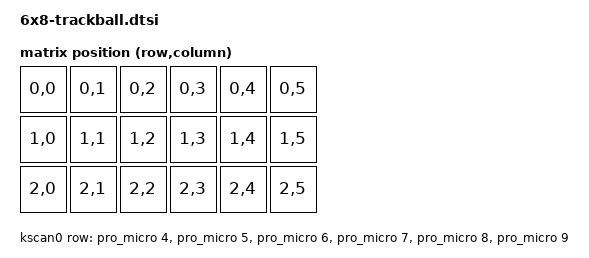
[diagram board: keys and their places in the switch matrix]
#include <dt-bindings/zmk/matrix_transform.h> // Put this with the other includes at the top of your dtsi

/ {
    chosen {
        zephyr,display = &oled;
        zmk,kscan = &kscan0;
        zmk,physical-layout = &kata0510_lily58_layout;
    };

    default_transform: keymap_transform_0 {
        compatible = "zmk,matrix-transform";
        columns = <16>;
        rows = <5>;
//| SW7  | SW6  | SW5  | SW4  | SW3   | SW2  | SW1  |           | SW1  | SW2  | SW3  | SW4  | SW5   | SW6  | SW7  | SW8  |         
//| SW14 | SW13 | SW12 | SW11 | SW10  | SW9  | SW8  |           | SW9  | SW10 | SW11 | SW12 | SW13  | SW14 | SW15 | SW16 | 
//| SW22 | SW21 | SW20 | SW19 | SW18  | SW17 | SW16  | SW15 |   | SW17 | SW18 | SW19 | SW20 | SW21  | SW22 | SW23 | SW24 |         
//| SW30 | SW29 | SW28 | SW27 | SW26  | SW25 | SW24  | SW23 |   | SW25 | SW26 | SW27 | SW28 | SW29  | SW30 | SW31 | SW32 |         
//| SW37 | SW36 | SW35 | SW34 | SW33  | SW32 | SW31  |                 | SW33 | SW34 | SW35 | SW36  | SW37 | SW38 | SW39 |         
//                     | SW39  | SW38 |                                              | SW40 | SW41  |        
//                                    | SW42 | SW41 | SW40 |           | SW42 |      | SW43 |
//                                           | SW44 | SW43 |              | SW44 | SW45 |

/ {
    default_transform: keymap_transform0 {
        compatible = "zmk,matrix-transform";
        columns = <6>;
        rows = <3>;
        map = <
        //  LKey 1 |LKey 2 |LKey 3      RKey 1 |RKey 2 |RKey 3
            RC(0,0) RC(0,1) RC(0,2)     RC(0,3) RC(0,4) RC(0,5)
        //  LKey 4 |LKey 5 |LKey 6      RKey 4 |RKey 5 |RKey 6
            RC(1,0) RC(1,1) RC(1,2)     RC(1,3) RC(1,4) RC(1,5)
        //  LKey 7 |LKey 8 |LKey 9      RKey 7 |RKey 8 |RKey 9
            RC(2,0) RC(2,1) RC(2,2)     RC(2,3) RC(2,4) RC(2,5)
        >;
    };
};

/ {
    kscan0: kscan0 {
        compatible = "zmk,kscan-gpio-matrix";
        diode-direction = "col2row";
        wakeup-source;

        row-gpios
            = <&pro_micro 4 (GPIO_ACTIVE_HIGH | GPIO_PULL_DOWN)>
            , <&pro_micro 5 (GPIO_ACTIVE_HIGH | GPIO_PULL_DOWN)>
            , <&pro_micro 6 (GPIO_ACTIVE_HIGH | GPIO_PULL_DOWN)>
            , <&pro_micro 7 (GPIO_ACTIVE_HIGH | GPIO_PULL_DOWN)>
            , <&pro_micro 8 (GPIO_ACTIVE_HIGH | GPIO_PULL_DOWN)>
            , <&pro_micro 9 (GPIO_ACTIVE_HIGH | GPIO_PULL_DOWN)>
            ;

    };
};
